VERSION 5.7 ;
  NOWIREEXTENSIONATPIN ON ;
  DIVIDERCHAR "/" ;
  BUSBITCHARS "[]" ;
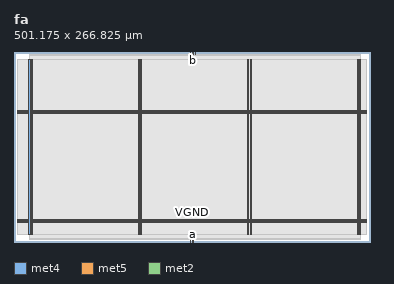
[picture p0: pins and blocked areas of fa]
MACRO fa
  CLASS BLOCK ;
  FOREIGN fa ;
  ORIGIN 0.000 0.000 ;
  SIZE 501.175 BY 266.825 ;
  PIN VGND
    DIRECTION INOUT ;
    USE GROUND ;
    PORT
      LAYER met4 ;
        RECT 24.340 10.640 25.940 255.920 ;
    END
    PORT
      LAYER met4 ;
        RECT 177.940 10.640 179.540 255.920 ;
    END
    PORT
      LAYER met4 ;
        RECT 331.540 10.640 333.140 255.920 ;
    END
    PORT
      LAYER met4 ;
        RECT 485.140 10.640 486.740 255.920 ;
    END
    PORT
      LAYER met5 ;
        RECT 5.280 30.030 495.660 31.630 ;
    END
    PORT
      LAYER met5 ;
        RECT 5.280 183.210 495.660 184.810 ;
    END
  END VGND
  PIN VPWR
    DIRECTION INOUT ;
    USE POWER ;
    PORT
      LAYER met4 ;
        RECT 21.040 10.640 22.640 255.920 ;
    END
    PORT
      LAYER met4 ;
        RECT 174.640 10.640 176.240 255.920 ;
    END
    PORT
      LAYER met4 ;
        RECT 328.240 10.640 329.840 255.920 ;
    END
    PORT
      LAYER met4 ;
        RECT 481.840 10.640 483.440 255.920 ;
    END
    PORT
      LAYER met5 ;
        RECT 5.280 26.730 495.660 28.330 ;
    END
    PORT
      LAYER met5 ;
        RECT 5.280 179.910 495.660 181.510 ;
    END
  END VPWR
  PIN a
    DIRECTION INPUT ;
    USE SIGNAL ;
    ANTENNAGATEAREA 0.213000 ;
    PORT
      LAYER met2 ;
        RECT 251.250 0.000 251.530 4.000 ;
    END
  END a
  PIN b
    DIRECTION INPUT ;
    USE SIGNAL ;
    ANTENNAGATEAREA 0.213000 ;
    PORT
      LAYER met2 ;
        RECT 251.250 262.825 251.530 266.825 ;
    END
  END b
  PIN cin
    DIRECTION INPUT ;
    USE SIGNAL ;
    ANTENNAGATEAREA 0.213000 ;
    PORT
      LAYER met2 ;
        RECT 248.030 0.000 248.310 4.000 ;
    END
  END cin
  PIN cout
    DIRECTION OUTPUT TRISTATE ;
    USE SIGNAL ;
    ANTENNADIFFAREA 0.795200 ;
    PORT
      LAYER met2 ;
        RECT 248.030 262.825 248.310 266.825 ;
    END
  END cout
  PIN s
    DIRECTION OUTPUT TRISTATE ;
    USE SIGNAL ;
    ANTENNADIFFAREA 0.795200 ;
    PORT
      LAYER met2 ;
        RECT 254.470 262.825 254.750 266.825 ;
    END
  END s
  OBS
      LAYER li1 ;
        RECT 5.520 10.795 495.420 255.765 ;
      LAYER met1 ;
        RECT 5.520 10.640 495.420 255.920 ;
      LAYER met2 ;
        RECT 21.070 262.545 247.750 262.825 ;
        RECT 248.590 262.545 250.970 262.825 ;
        RECT 251.810 262.545 254.190 262.825 ;
        RECT 255.030 262.545 486.710 262.825 ;
        RECT 21.070 4.280 486.710 262.545 ;
        RECT 21.070 4.000 247.750 4.280 ;
        RECT 248.590 4.000 250.970 4.280 ;
        RECT 251.810 4.000 486.710 4.280 ;
      LAYER met3 ;
        RECT 21.050 10.715 486.730 255.845 ;
  END
END fa
END LIBRARY

